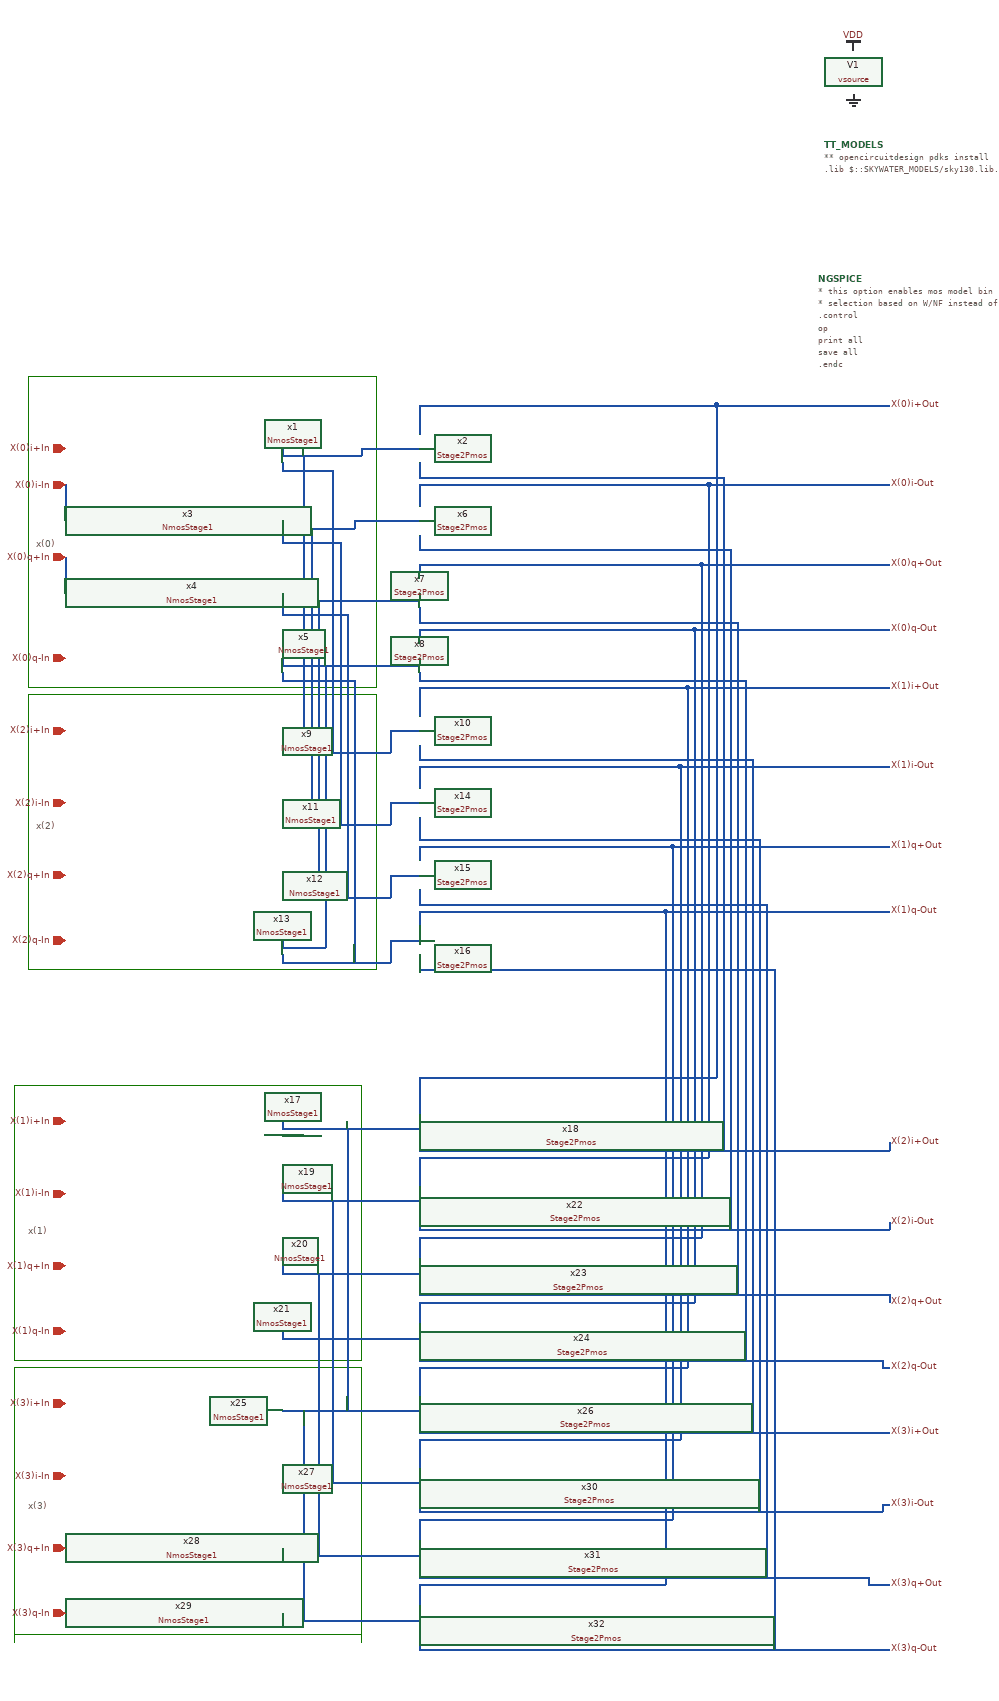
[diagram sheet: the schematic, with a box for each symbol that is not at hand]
v {xschem version=3.1.0 file_version=1.2
}
G {}
K {}
V {}
S {}
E {}
L 4 -650 -130 -180 -130 {}
L 4 -180 -130 -180 300 {}
L 4 -660 300 -180 300 {}
L 4 -660 -130 -660 300 {}
L 4 -660 -130 -650 -130 {}
L 4 -660 310 -180 310 {}
L 4 -180 310 -180 690 {}
L 4 -660 310 -660 690 {}
L 4 -660 690 -180 690 {}
L 4 -680 850 -200 850 {}
L 4 -200 850 -200 1230 {}
L 4 -680 850 -680 1230 {}
L 4 -680 1230 -200 1230 {}
L 4 -680 1240 -200 1240 {}
L 4 -200 1240 -200 1620 {}
L 4 -680 1240 -680 1620 {}
L 4 -680 1610 -200 1610 {}
T {x(0)} -650 90 0 0 0.4 0.4 {}
T {x(2)} -650 480 0 0 0.4 0.4 {}
T {x(1)} -660 1040 0 0 0.4 0.4 {}
T {x(3)} -660 1420 0 0 0.4 0.4 {}
N -120 -90 210 -90 {
lab=X(0)i+Out}
N -310 180 -120 180 {
lab=#net1}
N -310 270 -120 270 {
lab=#net2}
N -120 20 210 20 {
lab=X(0)i-Out}
N -120 130 210 130 {
lab=X(0)q+Out}
N -120 220 210 220 {
lab=X(0)q-Out}
N -120 410 210 410 {
lab=X(1)i-Out}
N -120 520 210 520 {
lab=X(1)q+Out}
N -120 610 210 610 {
lab=X(1)q-Out}
N -120 840 -120 890 {
lab=X(0)i+Out}
N -120 840 210 840 {
lab=X(0)i+Out}
N -310 910 -130 910 {
lab=#net3}
N -130 910 -120 910 {
lab=#net3}
N -310 1010 -120 1010 {
lab=#net4}
N -310 1110 -120 1110 {
lab=#net5}
N -310 1200 -120 1200 {
lab=#net6}
N -120 950 -120 990 {
lab=X(0)i-Out}
N -120 950 210 950 {
lab=X(0)i-Out}
N -120 1060 -120 1090 {
lab=X(0)q+Out}
N -120 1060 210 1060 {
lab=X(0)q+Out}
N -120 1150 -120 1180 {
lab=X(0)q-Out}
N -120 1150 210 1150 {
lab=X(0)q-Out}
N -310 1300 -130 1300 {
lab=#net3}
N -130 1300 -120 1300 {
lab=#net3}
N -310 1400 -120 1400 {
lab=#net4}
N -310 1500 -120 1500 {
lab=#net5}
N -310 1590 -120 1590 {
lab=#net3}
N -120 1340 -120 1380 {
lab=X(1)i-Out}
N -120 1340 210 1340 {
lab=X(1)i-Out}
N -120 1450 -120 1480 {
lab=X(1)q+Out}
N -120 1450 210 1450 {
lab=X(1)q+Out}
N -120 1540 -120 1570 {
lab=X(1)q-Out}
N -120 1540 210 1540 {
lab=X(1)q-Out}
N -220 920 -220 1300 {
lab=#net3}
N -220 910 -220 920 {
lab=#net3}
N -240 1010 -240 1400 {
lab=#net4}
N -260 1110 -260 1500 {
lab=#net5}
N -280 1300 -280 1590 {
lab=#net3}
N 210 840 290 840 {
lab=X(0)i+Out}
N 290 -90 290 840 {
lab=X(0)i+Out}
N 210 -90 290 -90 {
lab=X(0)i+Out}
N 290 -90 530 -90 {
lab=X(0)i+Out}
N 210 950 280 950 {
lab=X(0)i-Out}
N 280 20 280 950 {
lab=X(0)i-Out}
N 210 20 280 20 {
lab=X(0)i-Out}
N 210 130 270 130 {
lab=X(0)q+Out}
N 270 130 270 1060 {
lab=X(0)q+Out}
N 210 1060 270 1060 {
lab=X(0)q+Out}
N 210 1150 260 1150 {
lab=X(0)q-Out}
N 260 220 260 1150 {
lab=X(0)q-Out}
N 210 220 260 220 {
lab=X(0)q-Out}
N 280 20 530 20 {
lab=X(0)i-Out}
N 270 130 530 130 {
lab=X(0)q+Out}
N 260 220 530 220 {
lab=X(0)q-Out}
N -120 310 -120 320 {
lab=X(1)i+Out}
N -120 300 250 300 {
lab=X(1)i+Out}
N -120 300 -120 310 {
lab=X(1)i+Out}
N 250 300 530 300 {
lab=X(1)i+Out}
N -120 1260 -120 1280 {
lab=X(1)i+Out}
N -120 1240 -120 1260 {
lab=X(1)i+Out}
N -120 1240 250 1240 {
lab=X(1)i+Out}
N 250 300 250 1240 {
lab=X(1)i+Out}
N 210 410 240 410 {
lab=X(1)i-Out}
N 240 410 240 1340 {
lab=X(1)i-Out}
N 210 1340 240 1340 {
lab=X(1)i-Out}
N 210 1450 230 1450 {
lab=X(1)q+Out}
N 230 520 230 1450 {
lab=X(1)q+Out}
N 210 520 230 520 {
lab=X(1)q+Out}
N 210 610 220 610 {
lab=X(1)q-Out}
N 220 610 220 1540 {
lab=X(1)q-Out}
N 210 1540 220 1540 {
lab=X(1)q-Out}
N 240 410 530 410 {
lab=X(1)i-Out}
N 230 520 530 520 {
lab=X(1)q+Out}
N 220 610 530 610 {
lab=X(1)q-Out}
N 520 1430 530 1430 {
lab=X(3)i-Out}
N -200 -30 -200 -20 {
lab=#net7}
N -200 -30 -120 -30 {
lab=#net7}
N -120 -90 -120 -50 {
lab=X(0)i+Out}
N -120 20 -120 50 {
lab=X(0)i-Out}
N -310 80 -210 80 {
lab=#net8}
N -210 70 -210 80 {
lab=#net8}
N -210 70 -120 70 {
lab=#net8}
N -120 130 -120 150 {
lab=X(0)q+Out}
N -120 170 -120 180 {
lab=#net1}
N -120 220 -120 240 {
lab=X(0)q-Out}
N -120 260 -120 270 {
lab=#net2}
N -120 320 -120 340 {
lab=X(1)i+Out}
N -120 410 -120 440 {
lab=X(1)i-Out}
N -120 520 -120 540 {
lab=X(1)q+Out}
N -120 610 -120 630 {
lab=X(1)q-Out}
N -120 900 -120 910 {
lab=#net3}
N -120 1000 -120 1010 {
lab=#net4}
N -120 1100 -120 1110 {
lab=#net5}
N -120 1190 -120 1200 {
lab=#net6}
N -120 1290 -120 1300 {
lab=#net3}
N -120 1390 -120 1400 {
lab=#net4}
N -120 1490 -120 1500 {
lab=#net5}
N -120 1580 -120 1590 {
lab=#net3}
N -120 1600 -120 1630 {
lab=X(3)q-Out}
N -120 1630 530 1630 {
lab=X(3)q-Out}
N -120 1520 -120 1530 {
lab=X(3)q+Out}
N -120 1530 500 1530 {
lab=X(3)q+Out}
N 500 1530 500 1540 {
lab=X(3)q+Out}
N 500 1540 530 1540 {
lab=X(3)q+Out}
N -120 1410 -120 1440 {
lab=X(3)i-Out}
N -120 1440 520 1440 {
lab=X(3)i-Out}
N 520 1430 520 1440 {
lab=X(3)i-Out}
N -120 1310 -120 1330 {
lab=X(3)i+Out}
N -120 1330 530 1330 {
lab=X(3)i+Out}
N -120 1210 -120 1230 {
lab=X(2)q-Out}
N -120 1230 520 1230 {
lab=X(2)q-Out}
N 520 1230 520 1240 {
lab=X(2)q-Out}
N 520 1240 530 1240 {
lab=X(2)q-Out}
N -120 1120 -120 1140 {
lab=X(2)q+Out}
N -120 1140 530 1140 {
lab=X(2)q+Out}
N 530 1140 530 1150 {
lab=X(2)q+Out}
N -120 1020 -120 1050 {
lab=X(2)i-Out}
N -120 1050 530 1050 {
lab=X(2)i-Out}
N 530 1040 530 1050 {
lab=X(2)i-Out}
N -120 920 -120 940 {
lab=X(2)i+Out}
N -120 940 530 940 {
lab=X(2)i+Out}
N 530 930 530 940 {
lab=X(2)i+Out}
N -120 -10 -120 10 {
lab=X(2)i+Out}
N -120 10 300 10 {
lab=X(2)i+Out}
N -120 90 -120 110 {
lab=X(2)i-Out}
N -120 190 -120 210 {
lab=X(2)q+Out}
N -120 210 320 210 {
lab=X(2)q+Out}
N -120 280 -120 290 {
lab=X(2)q-Out}
N -120 290 330 290 {
lab=X(2)q-Out}
N -120 380 -120 400 {
lab=X(3)i+Out}
N -120 400 340 400 {
lab=X(3)i+Out}
N -120 480 -120 510 {
lab=X(3)i-Out}
N -120 510 350 510 {
lab=X(3)i-Out}
N -120 580 -120 600 {
lab=X(3)q+Out}
N -120 600 360 600 {
lab=X(3)q+Out}
N -120 670 -120 690 {
lab=X(3)q-Out}
N -120 690 370 690 {
lab=X(3)q-Out}
N 300 10 300 940 {
lab=X(2)i+Out}
N -120 110 310 110 {
lab=X(2)i-Out}
N 310 110 310 260 {
lab=X(2)i-Out}
N 310 260 310 1050 {
lab=X(2)i-Out}
N 320 210 320 1140 {
lab=X(2)q+Out}
N 330 290 330 1230 {
lab=X(2)q-Out}
N 340 400 340 1330 {
lab=X(3)i+Out}
N 350 510 350 1440 {
lab=X(3)i-Out}
N 360 600 360 1530 {
lab=X(3)q+Out}
N 370 690 370 1630 {
lab=X(3)q-Out}
N -310 370 -280 370 {
lab=#net7}
N -310 470 -270 470 {
lab=#net8}
N -270 80 -270 470 {
lab=#net8}
N -310 570 -260 570 {
lab=#net1}
N -260 180 -260 570 {
lab=#net1}
N -310 660 -250 660 {
lab=#net2}
N -250 270 -250 660 {
lab=#net2}
N -310 390 -160 390 {
lab=#net9}
N -160 360 -160 390 {
lab=#net9}
N -160 360 -120 360 {
lab=#net9}
N -310 490 -160 490 {
lab=#net10}
N -160 460 -160 490 {
lab=#net10}
N -160 460 -120 460 {
lab=#net10}
N -310 590 -160 590 {
lab=#net11}
N -160 560 -160 590 {
lab=#net11}
N -160 560 -120 560 {
lab=#net11}
N -310 680 -160 680 {
lab=#net12}
N -160 650 -160 680 {
lab=#net12}
N -160 650 -120 650 {
lab=#net12}
N -240 0 -240 390 {
lab=#net9}
N -310 100 -230 100 {
lab=#net10}
N -230 100 -230 490 {
lab=#net10}
N -310 200 -220 200 {
lab=#net11}
N -220 200 -220 590 {
lab=#net11}
N -310 290 -210 290 {
lab=#net12}
N -210 290 -210 680 {
lab=#net12}
N -280 -10 -280 370 {
lab=#net7}
N -280 -20 -280 -10 {
lab=#net7}
N -310 0 -240 0 {
lab=#net9}
N -310 -20 -200 -20 {
lab=#net7}
N -310 1580 -310 1590 {
lab=#net3}
N -610 1570 -610 1580 {
lab=X(3)q-In}
N -310 1490 -310 1500 {
lab=#net5}
N -610 1480 -610 1490 {
lab=X(3)q+In}
N -310 1390 -310 1400 {
lab=#net4}
N -310 1190 -310 1200 {
lab=#net6}
N -310 1100 -310 1110 {
lab=#net5}
N -310 1000 -310 1010 {
lab=#net4}
N -310 900 -310 910 {
lab=#net3}
N -310 650 -310 660 {
lab=#net2}
N -310 670 -310 680 {
lab=#net12}
N -310 560 -310 570 {
lab=#net1}
N -310 580 -310 590 {
lab=#net11}
N -310 360 -310 370 {
lab=#net7}
N -310 380 -310 390 {
lab=#net9}
N -310 460 -310 470 {
lab=#net8}
N -310 480 -310 490 {
lab=#net10}
N -310 280 -310 290 {
lab=#net12}
N -310 260 -310 270 {
lab=#net2}
N -610 120 -610 170 {
lab=X(0)q+In}
N -310 190 -310 200 {
lab=#net11}
N -310 170 -310 180 {
lab=#net1}
N -610 20 -610 70 {
lab=X(0)i-In}
N -310 90 -310 100 {
lab=#net10}
N -310 70 -310 80 {
lab=#net8}
N -310 -10 -310 -0 {
lab=#net9}
N -310 -30 -310 -20 {
lab=#net7}
N -310 920 -280 920 {
lab=#net13}
C {devices/code.sym} 440 -450 0 0 {name=TT_MODELS
only_toplevel=true
format="tcleval( @value )"
value="
** opencircuitdesign pdks install
.lib $::SKYWATER_MODELS/sky130.lib.spice tt

"
spice_ignore=false}
C {devices/vsource.sym} 480 -550 0 0 {name=V1 value=5}
C {devices/vdd.sym} 480 -580 0 0 {name=l4 lab=VDD}
C {devices/gnd.sym} 480 -520 0 0 {name=l5 lab=GND}
C {FinalProject/NmosStage1.sym} -460 -20 0 0 {name=x1}
C {FinalProject/Stage2Pmos.sym} 30 -30 0 1 {name=x2}
C {FinalProject/NmosStage1.sym} -460 80 0 0 {name=x3}
C {FinalProject/NmosStage1.sym} -460 180 0 0 {name=x4}
C {FinalProject/NmosStage1.sym} -460 270 0 0 {name=x5}
C {FinalProject/Stage2Pmos.sym} 30 70 0 1 {name=x6}
C {FinalProject/Stage2Pmos.sym} 30 170 0 1 {name=x7}
C {FinalProject/Stage2Pmos.sym} 30 260 0 1 {name=x8}
C {FinalProject/NmosStage1.sym} -460 370 0 0 {name=x9}
C {FinalProject/Stage2Pmos.sym} 30 360 0 1 {name=x10}
C {FinalProject/NmosStage1.sym} -460 470 0 0 {name=x11}
C {FinalProject/NmosStage1.sym} -460 570 0 0 {name=x12}
C {FinalProject/NmosStage1.sym} -460 660 0 0 {name=x13}
C {FinalProject/Stage2Pmos.sym} 30 460 0 1 {name=x14}
C {FinalProject/Stage2Pmos.sym} 30 560 0 1 {name=x15}
C {FinalProject/Stage2Pmos.sym} 30 650 0 1 {name=x16}
C {FinalProject/NmosStage1.sym} -460 910 0 0 {name=x17}
C {FinalProject/Stage2Pmos.sym} 30 900 0 1 {name=x18}
C {FinalProject/NmosStage1.sym} -460 1010 0 0 {name=x19}
C {FinalProject/NmosStage1.sym} -460 1110 0 0 {name=x20}
C {FinalProject/NmosStage1.sym} -460 1200 0 0 {name=x21}
C {FinalProject/Stage2Pmos.sym} 30 1000 0 1 {name=x22}
C {FinalProject/Stage2Pmos.sym} 30 1100 0 1 {name=x23}
C {FinalProject/Stage2Pmos.sym} 30 1190 0 1 {name=x24}
C {FinalProject/NmosStage1.sym} -460 1300 0 0 {name=x25}
C {FinalProject/Stage2Pmos.sym} 30 1290 0 1 {name=x26}
C {FinalProject/NmosStage1.sym} -460 1400 0 0 {name=x27}
C {FinalProject/NmosStage1.sym} -460 1500 0 0 {name=x28}
C {FinalProject/NmosStage1.sym} -460 1590 0 0 {name=x29}
C {FinalProject/Stage2Pmos.sym} 30 1390 0 1 {name=x30}
C {FinalProject/Stage2Pmos.sym} 30 1490 0 1 {name=x31}
C {FinalProject/Stage2Pmos.sym} 30 1580 0 1 {name=x32}
C {devices/lab_pin.sym} 530 -90 2 0 {name=p1 sig_type=std_logic lab=X(0)i+Out}
C {devices/lab_pin.sym} 530 20 2 0 {name=p2 sig_type=std_logic lab=X(0)i-Out}
C {devices/lab_pin.sym} 530 130 2 0 {name=p3 sig_type=std_logic lab=X(0)q+Out}
C {devices/lab_pin.sym} 530 220 2 0 {name=p4 sig_type=std_logic lab=X(0)q-Out}
C {devices/lab_pin.sym} 530 300 2 0 {name=p5 sig_type=std_logic lab=X(1)i+Out}
C {devices/lab_pin.sym} 530 410 2 0 {name=p6 sig_type=std_logic lab=X(1)i-Out}
C {devices/lab_pin.sym} 530 520 2 0 {name=p7 sig_type=std_logic lab=X(1)q+Out}
C {devices/lab_pin.sym} 530 610 2 0 {name=p8 sig_type=std_logic lab=X(1)q-Out}
C {devices/lab_pin.sym} 530 930 2 0 {name=p9 sig_type=std_logic lab=X(2)i+Out}
C {devices/lab_pin.sym} 530 1040 2 0 {name=p10 sig_type=std_logic lab=X(2)i-Out}
C {devices/lab_pin.sym} 530 1150 2 0 {name=p11 sig_type=std_logic lab=X(2)q+Out}
C {devices/lab_pin.sym} 530 1240 2 0 {name=p12 sig_type=std_logic lab=X(2)q-Out}
C {devices/lab_pin.sym} 530 1330 2 0 {name=p13 sig_type=std_logic lab=X(3)i+Out}
C {devices/lab_pin.sym} 530 1430 2 0 {name=p14 sig_type=std_logic lab=X(3)i-Out}
C {devices/lab_pin.sym} 530 1540 2 0 {name=p15 sig_type=std_logic lab=X(3)q+Out}
C {devices/lab_pin.sym} 530 1630 2 0 {name=p16 sig_type=std_logic lab=X(3)q-Out}
C {devices/iopin.sym} -610 -30 2 0 {name=p33 lab=X(0)i+In}
C {devices/code.sym} 431.25 -264.375 0 0 {name=NGSPICE
only_toplevel=true
value="* this option enables mos model bin 
* selection based on W/NF instead of W
.control
op
print all
save all
.endc
"}
C {devices/iopin.sym} -610 20 2 0 {name=p17 lab=X(0)i-In}
C {devices/iopin.sym} -610 120 2 0 {name=p34 lab=X(0)q+In}
C {devices/iopin.sym} -610 260 2 0 {name=p35 lab=X(0)q-In}
C {devices/iopin.sym} -610 360 2 0 {name=p18 lab=X(2)i+In}
C {devices/iopin.sym} -610 460 2 0 {name=p19 lab=X(2)i-In}
C {devices/iopin.sym} -610 560 2 0 {name=p20 lab=X(2)q+In}
C {devices/iopin.sym} -610 650 2 0 {name=p21 lab=X(2)q-In}
C {devices/iopin.sym} -610 900 2 0 {name=p22 lab=X(1)i+In}
C {devices/iopin.sym} -610 1000 2 0 {name=p23 lab=X(1)i-In}
C {devices/iopin.sym} -610 1100 2 0 {name=p24 lab=X(1)q+In}
C {devices/iopin.sym} -610 1190 2 0 {name=p36 lab=X(1)q-In}
C {devices/iopin.sym} -610 1290 2 0 {name=p25 lab=X(3)i+In}
C {devices/iopin.sym} -610 1390 2 0 {name=p26 lab=X(3)i-In}
C {devices/iopin.sym} -610 1490 2 0 {name=p27 lab=X(3)q+In}
C {devices/iopin.sym} -610 1580 2 0 {name=p28 lab=X(3)q-In}
